VERSION 5.7 ;
BUSBITCHARS "[]" ;
DIVIDERCHAR "/" ;

PROPERTYDEFINITIONS
  LAYER LEF58_TYPE STRING ;
  LAYER LEF58_ENCLOSURE STRING ;
  LAYER LEF58_SPACING STRING ;
  LAYER LEF58_WIDTH STRING ;
END PROPERTYDEFINITIONS

UNITS
  TIME NANOSECONDS 1 ;
  CAPACITANCE PICOFARADS 1 ;
  RESISTANCE OHMS 1 ;
  DATABASE MICRONS 1000 ;
END UNITS
MANUFACTURINGGRID 0.005 ;

SITE core
  SIZE 0.56 BY 5.6 ;
  CLASS CORE ;
  SYMMETRY X Y ;
END core

LAYER OverlapCheck
  TYPE OVERLAP ;
END OverlapCheck

LAYER WN
  TYPE MASTERSLICE ;
  PROPERTY LEF58_TYPE "TYPE NWELL ;" ;
  PROPERTY LEF58_SPACING "SPACING 2.8 ;" ;
  PROPERTY LEF58_WIDTH "WIDTH 0.86 ;" ;
END WN

LAYER ACTIVE
  TYPE MASTERSLICE ;
  PROPERTY LEF58_TYPE "TYPE DIFFUSION ;" ;
END ACTIVE

LAYER XP
  TYPE IMPLANT ;
  WIDTH 0.44 ;
  SPACING 0.44 ;
END XP

LAYER XN
  TYPE IMPLANT ;
  WIDTH 0.44 ;
  SPACING 0.44 ;
END XN

LAYER GC
  TYPE MASTERSLICE ;
END GC

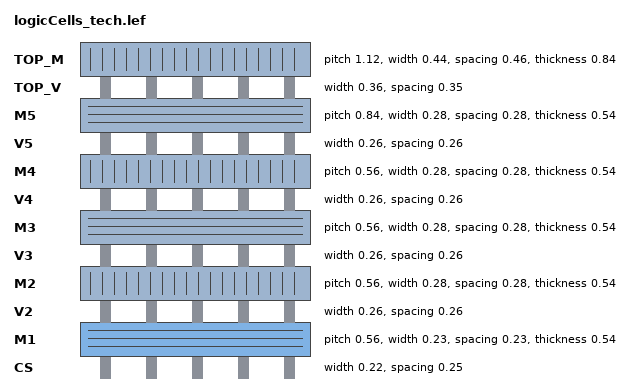
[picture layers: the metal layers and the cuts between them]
LAYER CS
  TYPE CUT ;
  SPACING 0.25 ;
  WIDTH 0.22 ;
  ENCLOSURE BELOW 0.1 0.1 ;
  ENCLOSURE ABOVE 0.06 0.005 ;
  ANTENNAMODEL OXIDE1 ;
END CS

LAYER M1
  TYPE ROUTING ;
  DIRECTION HORIZONTAL ;
  PITCH 0.56 0.56 ;
  WIDTH 0.23 ;
  OFFSET 0.28 ;
  AREA 0.202 ;
  SPACING 0.23 ;
  SPACING 0.6 RANGE 10 10000 ;
  SPACING 0.23 SAMENET ;
  RESISTANCE RPERSQ 0.08 ;
  CAPACITANCE CPERSQDIST 3.51e-05 ;
  HEIGHT 1.05 ;
  THICKNESS 0.54 ;
  ANTENNAMODEL OXIDE1 ;
    ANTENNASIDEAREARATIO 400 ;
    ANTENNADIFFSIDEAREARATIO PWL ( ( 0 400 ) ( 0.203 400 ) ( 0.203001 2281.2 ) ( 1.203 2681.2 ) ) ;
END M1

LAYER V2
  TYPE CUT ;
  SPACING 0.26 ;
  SPACING 0 LAYER CS ;
  WIDTH 0.26 ;
  ENCLOSURE BELOW 0.06 0.01 ;
  ENCLOSURE ABOVE 0.06 0.01 ;
  ANTENNAMODEL OXIDE1 ;
    ANTENNAAREARATIO 20 ;
    ANTENNADIFFAREARATIO PWL ( ( 0 20 ) ( 0.203 20 ) ( 0.203001 91.9161 ) ( 1.203 175.246 ) ) ;
END V2

LAYER M2
  TYPE ROUTING ;
  DIRECTION VERTICAL ;
  PITCH 0.56 0.56 ;
  WIDTH 0.28 ;
  OFFSET 0.28 ;
  AREA 0.202 ;
  SPACING 0.28 ;
  SPACING 0.6 RANGE 10 10000 ;
  SPACING 0.28 SAMENET ;
  RESISTANCE RPERSQ 0.08 ;
  CAPACITANCE CPERSQDIST 1.46e-05 ;
  HEIGHT 2.41 ;
  THICKNESS 0.54 ;
  ANTENNAMODEL OXIDE1 ;
    ANTENNASIDEAREARATIO 400 ;
    ANTENNADIFFSIDEAREARATIO PWL ( ( 0 400 ) ( 0.203 400 ) ( 0.203001 2281.2 ) ( 1.203 2681.2 ) ) ;
END M2

LAYER V3
  TYPE CUT ;
  SPACING 0.26 ;
  SPACING 0 SAMENET LAYER V2 STACK ;
  WIDTH 0.26 ;
  ENCLOSURE BELOW 0.06 0.01 ;
  ENCLOSURE ABOVE 0.06 0.01 ;
  ANTENNAMODEL OXIDE1 ;
    ANTENNAAREARATIO 20 ;
    ANTENNADIFFAREARATIO PWL ( ( 0 20 ) ( 0.203 20 ) ( 0.203001 91.9161 ) ( 1.203 175.246 ) ) ;
END V3

LAYER M3
  TYPE ROUTING ;
  DIRECTION HORIZONTAL ;
  PITCH 0.56 0.56 ;
  WIDTH 0.28 ;
  OFFSET 0.28 ;
  AREA 0.202 ;
  SPACING 0.28 ;
  SPACING 0.6 RANGE 10 10000 ;
  SPACING 0.28 SAMENET ;
  RESISTANCE RPERSQ 0.08 ;
  CAPACITANCE CPERSQDIST 9.24e-06 ;
  HEIGHT 3.77 ;
  THICKNESS 0.54 ;
  ANTENNAMODEL OXIDE1 ;
    ANTENNASIDEAREARATIO 400 ;
    ANTENNADIFFSIDEAREARATIO PWL ( ( 0 400 ) ( 0.203 400 ) ( 0.203001 2281.2 ) ( 1.203 2681.2 ) ) ;
END M3

LAYER V4
  TYPE CUT ;
  SPACING 0.26 ;
  SPACING 0 SAMENET LAYER V3 STACK ;
  WIDTH 0.26 ;
  ENCLOSURE BELOW 0.06 0.01 ;
  ENCLOSURE ABOVE 0.06 0.01 ;
  ANTENNAMODEL OXIDE1 ;
    ANTENNAAREARATIO 20 ;
    ANTENNADIFFAREARATIO PWL ( ( 0 20 ) ( 0.203 20 ) ( 0.203001 91.9161 ) ( 1.203 175.246 ) ) ;
END V4

LAYER M4
  TYPE ROUTING ;
  DIRECTION VERTICAL ;
  PITCH 0.56 0.56 ;
  WIDTH 0.28 ;
  OFFSET 0.28 ;
  AREA 0.202 ;
  SPACING 0.28 ;
  SPACING 0.6 RANGE 10 10000 ;
  SPACING 0.28 SAMENET ;
  RESISTANCE RPERSQ 0.08 ;
  CAPACITANCE CPERSQDIST 6.75e-06 ;
  HEIGHT 5.13 ;
  THICKNESS 0.54 ;
  ANTENNAMODEL OXIDE1 ;
    ANTENNASIDEAREARATIO 400 ;
    ANTENNADIFFSIDEAREARATIO PWL ( ( 0 400 ) ( 0.203 400 ) ( 0.203001 2281.2 ) ( 1.203 2681.2 ) ) ;
END M4

LAYER V5
  TYPE CUT ;
  SPACING 0.26 ;
  SPACING 0 SAMENET LAYER V4 STACK ;
  WIDTH 0.26 ;
  ENCLOSURE BELOW 0.06 0.01 ;
  ENCLOSURE ABOVE 0.06 0.01 ;
  ANTENNAMODEL OXIDE1 ;
    ANTENNAAREARATIO 20 ;
    ANTENNADIFFAREARATIO PWL ( ( 0 20 ) ( 0.203 20 ) ( 0.203001 91.9161 ) ( 1.203 175.246 ) ) ;
END V5

LAYER M5
  TYPE ROUTING ;
  DIRECTION HORIZONTAL ;
  PITCH 0.84 0.84 ;
  WIDTH 0.28 ;
  OFFSET 0.42 ;
  AREA 0.202 ;
  SPACING 0.28 ;
  SPACING 0.6 RANGE 10 10000 ;
  SPACING 0.28 SAMENET ;
  RESISTANCE RPERSQ 0.08 ;
  CAPACITANCE CPERSQDIST 5.32e-06 ;
  HEIGHT 6.49 ;
  THICKNESS 0.54 ;
  ANTENNAMODEL OXIDE1 ;
    ANTENNASIDEAREARATIO 400 ;
    ANTENNADIFFSIDEAREARATIO PWL ( ( 0 400 ) ( 0.203 400 ) ( 0.203001 2281.2 ) ( 1.203 2681.2 ) ) ;
END M5

LAYER TOP_V
  TYPE CUT ;
  SPACING 0.35 ;
  SPACING 0 SAMENET LAYER V5 STACK ;
  WIDTH 0.36 ;
  ENCLOSURE BELOW 0.06 0.01 ;
  ENCLOSURE ABOVE 0.09 0.09 ;
  ANTENNAMODEL OXIDE1 ;
    ANTENNAAREARATIO 20 ;
    ANTENNADIFFAREARATIO PWL ( ( 0 20 ) ( 0.203 20 ) ( 0.203001 91.9161 ) ( 1.203 175.246 ) ) ;
END TOP_V

LAYER TOP_M
  TYPE ROUTING ;
  DIRECTION VERTICAL ;
  PITCH 1.12 1.12 ;
  WIDTH 0.44 ;
  OFFSET 0.56 ;
  AREA 0.562 ;
  SPACING 0.46 ;
  SPACING 0.6 RANGE 10 10000 ;
  SPACING 0.46 SAMENET ;
  RESISTANCE RPERSQ 0.04 ;
  CAPACITANCE CPERSQDIST 4.389e-06 ;
  HEIGHT 7.83 ;
  THICKNESS 0.84 ;
  ANTENNAMODEL OXIDE1 ;
    ANTENNASIDEAREARATIO 400 ;
    ANTENNADIFFSIDEAREARATIO PWL ( ( 0 400 ) ( 0.203 400 ) ( 0.203001 31624 ) ( 1.203 39624 ) ) ;
END TOP_M

VIARULE ML_M5_LD GENERATE
  LAYER M5 ;
    ENCLOSURE 0.1 0.1 ;
  LAYER TOP_M ;
    ENCLOSURE 0.1 0.1 ;
  LAYER TOP_V ;
    RECT -0.18 -0.18 0.18 0.18 ;
    SPACING 0.71 BY 0.71 ;
END ML_M5_LD

VIARULE M5_M4_LD GENERATE
  LAYER M4 ;
    ENCLOSURE 0.1 0.1 ;
  LAYER M5 ;
    ENCLOSURE 0.1 0.1 ;
  LAYER V5 ;
    RECT -0.13 -0.13 0.13 0.13 ;
    SPACING 0.52 BY 0.52 ;
END M5_M4_LD

VIARULE M4_M3_LD GENERATE
  LAYER M3 ;
    ENCLOSURE 0.1 0.1 ;
  LAYER M4 ;
    ENCLOSURE 0.1 0.1 ;
  LAYER V4 ;
    RECT -0.13 -0.13 0.13 0.13 ;
    SPACING 0.52 BY 0.52 ;
END M4_M3_LD

VIARULE M3_M2_LD GENERATE
  LAYER M2 ;
    ENCLOSURE 0.1 0.1 ;
  LAYER M3 ;
    ENCLOSURE 0.1 0.1 ;
  LAYER V3 ;
    RECT -0.13 -0.13 0.13 0.13 ;
    SPACING 0.52 BY 0.52 ;
END M3_M2_LD

VIARULE M2_M1_LD GENERATE
  LAYER M1 ;
    ENCLOSURE 0.1 0.1 ;
  LAYER M2 ;
    ENCLOSURE 0.1 0.1 ;
  LAYER V2 ;
    RECT -0.13 -0.13 0.13 0.13 ;
    SPACING 0.52 BY 0.52 ;
END M2_M1_LD

VIARULE ML_M5_S GENERATE DEFAULT
  LAYER M5 ;
    ENCLOSURE 0.01 0.01 ;
  LAYER TOP_M ;
    ENCLOSURE 0.09 0.09 ;
  LAYER TOP_V ;
    RECT -0.18 -0.18 0.18 0.18 ;
    SPACING 0.71 BY 0.71 ;
END ML_M5_S

VIARULE M5_M4_S GENERATE DEFAULT
  LAYER M4 ;
    ENCLOSURE 0.01 0.01 ;
  LAYER M5 ;
    ENCLOSURE 0.01 0.01 ;
  LAYER V5 ;
    RECT -0.13 -0.13 0.13 0.13 ;
    SPACING 0.52 BY 0.52 ;
END M5_M4_S

VIARULE M4_M3_S GENERATE DEFAULT
  LAYER M3 ;
    ENCLOSURE 0.01 0.01 ;
  LAYER M4 ;
    ENCLOSURE 0.01 0.01 ;
  LAYER V4 ;
    RECT -0.13 -0.13 0.13 0.13 ;
    SPACING 0.52 BY 0.52 ;
END M4_M3_S

VIARULE M3_M2_S GENERATE DEFAULT
  LAYER M2 ;
    ENCLOSURE 0.01 0.01 ;
  LAYER M3 ;
    ENCLOSURE 0.01 0.01 ;
  LAYER V3 ;
    RECT -0.13 -0.13 0.13 0.13 ;
    SPACING 0.52 BY 0.52 ;
END M3_M2_S

VIARULE M2_M1_S GENERATE DEFAULT
  LAYER M1 ;
    ENCLOSURE 0.01 0.01 ;
  LAYER M2 ;
    ENCLOSURE 0.01 0.01 ;
  LAYER V2 ;
    RECT -0.13 -0.13 0.13 0.13 ;
    SPACING 0.52 BY 0.52 ;
END M2_M1_S

VIARULE ML_M5 GENERATE
  LAYER M5 ;
    ENCLOSURE 0.06 0.06 ;
  LAYER TOP_M ;
    ENCLOSURE 0.09 0.09 ;
  LAYER TOP_V ;
    RECT -0.18 -0.18 0.18 0.18 ;
    SPACING 0.71 BY 0.71 ;
END ML_M5

VIARULE M5_M4 GENERATE
  LAYER M4 ;
    ENCLOSURE 0.06 0.06 ;
  LAYER M5 ;
    ENCLOSURE 0.06 0.06 ;
  LAYER V5 ;
    RECT -0.13 -0.13 0.13 0.13 ;
    SPACING 0.52 BY 0.52 ;
END M5_M4

VIARULE M4_M3 GENERATE
  LAYER M3 ;
    ENCLOSURE 0.06 0.06 ;
  LAYER M4 ;
    ENCLOSURE 0.06 0.06 ;
  LAYER V4 ;
    RECT -0.13 -0.13 0.13 0.13 ;
    SPACING 0.52 BY 0.52 ;
END M4_M3

VIARULE M3_M2 GENERATE
  LAYER M2 ;
    ENCLOSURE 0.06 0.06 ;
  LAYER M3 ;
    ENCLOSURE 0.06 0.06 ;
  LAYER V3 ;
    RECT -0.13 -0.13 0.13 0.13 ;
    SPACING 0.52 BY 0.52 ;
END M3_M2

VIARULE M2_M1 GENERATE
  LAYER M1 ;
    ENCLOSURE 0.06 0.06 ;
  LAYER M2 ;
    ENCLOSURE 0.06 0.06 ;
  LAYER V2 ;
    RECT -0.13 -0.13 0.13 0.13 ;
    SPACING 0.52 BY 0.52 ;
END M2_M1

VIARULE M1_PO_4X GENERATE
  LAYER GC ;
    ENCLOSURE 0.1 0.1 ;
  LAYER M1 ;
    ENCLOSURE 0.06 0.06 ;
  LAYER CS ;
    RECT -0.11 -0.11 0.11 0.11 ;
    SPACING 0.5 BY 0.5 ;
END M1_PO_4X

VIARULE M1_PO GENERATE
  LAYER GC ;
    ENCLOSURE 0.1 0.1 ;
  LAYER M1 ;
    ENCLOSURE 0.06 0.06 ;
  LAYER CS ;
    RECT -0.11 -0.11 0.11 0.11 ;
    SPACING 0.47 BY 0.47 ;
END M1_PO

VIARULE PTAP_4X_LG GENERATE
  LAYER ACTIVE ;
    ENCLOSURE 0.1 0.1 ;
  LAYER M1 ;
    ENCLOSURE 0.06 0.06 ;
  LAYER CS ;
    RECT -0.11 -0.11 0.11 0.11 ;
    SPACING 0.5 BY 0.5 ;
END PTAP_4X_LG

VIARULE PTAP_4X GENERATE
  LAYER ACTIVE ;
    ENCLOSURE 0.1 0.1 ;
  LAYER M1 ;
    ENCLOSURE 0.06 0.06 ;
  LAYER CS ;
    RECT -0.11 -0.11 0.11 0.11 ;
    SPACING 0.5 BY 0.5 ;
END PTAP_4X

VIARULE PTAP_LG GENERATE
  LAYER ACTIVE ;
    ENCLOSURE 0.1 0.1 ;
  LAYER M1 ;
    ENCLOSURE 0.06 0.06 ;
  LAYER CS ;
    RECT -0.11 -0.11 0.11 0.11 ;
    SPACING 0.47 BY 0.47 ;
END PTAP_LG

VIARULE PTAP GENERATE
  LAYER ACTIVE ;
    ENCLOSURE 0.1 0.1 ;
  LAYER M1 ;
    ENCLOSURE 0.06 0.06 ;
  LAYER CS ;
    RECT -0.11 -0.11 0.11 0.11 ;
    SPACING 0.47 BY 0.47 ;
END PTAP

VIARULE NTAP_4X_LG GENERATE
  LAYER ACTIVE ;
    ENCLOSURE 0.1 0.1 ;
  LAYER M1 ;
    ENCLOSURE 0.06 0.06 ;
  LAYER CS ;
    RECT -0.11 -0.11 0.11 0.11 ;
    SPACING 0.5 BY 0.5 ;
END NTAP_4X_LG

VIARULE NTAP_4X GENERATE
  LAYER ACTIVE ;
    ENCLOSURE 0.1 0.1 ;
  LAYER M1 ;
    ENCLOSURE 0.06 0.06 ;
  LAYER CS ;
    RECT -0.11 -0.11 0.11 0.11 ;
    SPACING 0.5 BY 0.5 ;
END NTAP_4X

VIARULE NTAP_LG GENERATE
  LAYER ACTIVE ;
    ENCLOSURE 0.1 0.1 ;
  LAYER M1 ;
    ENCLOSURE 0.06 0.06 ;
  LAYER CS ;
    RECT -0.11 -0.11 0.11 0.11 ;
    SPACING 0.47 BY 0.47 ;
END NTAP_LG

VIARULE NTAP GENERATE
  LAYER ACTIVE ;
    ENCLOSURE 0.1 0.1 ;
  LAYER M1 ;
    ENCLOSURE 0.06 0.06 ;
  LAYER CS ;
    RECT -0.11 -0.11 0.11 0.11 ;
    SPACING 0.47 BY 0.47 ;
END NTAP

VIARULE M1_WN GENERATE
  LAYER ACTIVE ;
    ENCLOSURE 0.1 0.1 ;
  LAYER M1 ;
    ENCLOSURE 0.06 0.06 ;
  LAYER CS ;
    RECT -0.11 -0.11 0.11 0.11 ;
    SPACING 0.47 BY 0.47 ;
END M1_WN


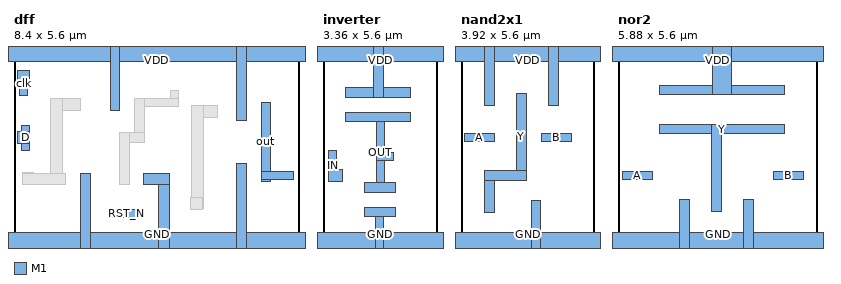
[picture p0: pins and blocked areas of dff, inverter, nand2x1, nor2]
MACRO dff
  CLASS CORE ;
  ORIGIN 0 0 ;
  FOREIGN dff 0 0 ;
  SIZE 8.4 BY 5.6 ;
  SYMMETRY X Y ;
  SITE core ;
  PIN D
    DIRECTION INOUT ;
    USE SIGNAL ;
    PORT
      LAYER M1 ;
        RECT 0.22 2.705 0.45 3.445 ;
        RECT 0.11 2.91 0.45 3.25 ;
    END
  END D
  PIN clk
    DIRECTION INPUT ;
    USE CLOCK ;
    PORT
      LAYER M1 ;
        RECT 0.115 4.705 0.455 5.045 ;
        RECT 0.17 4.32 0.4 5.045 ;
    END
  END clk
  PIN out
    DIRECTION INOUT ;
    USE SIGNAL ;
    PORT
      LAYER M1 ;
        RECT 7.28 1.845 8.24 2.075 ;
        RECT 7.28 1.795 7.56 4.105 ;
    END
  END out
  PIN RST_N
    DIRECTION INPUT ;
    USE SIGNAL ;
    PORT
      LAYER M1 ;
        RECT 2.87 0.725 3.78 0.955 ;
    END
  END RST_N
  PIN VDD
    DIRECTION INOUT ;
    USE POWER ;
    SHAPE ABUTMENT ;
    PORT
      LAYER M1 ;
        RECT -0.28 5.32 8.68 5.88 ;
        RECT 6.56 3.585 6.84 5.88 ;
        RECT 2.835 3.89 3.115 5.88 ;
    END
  END VDD
  PIN GND
    DIRECTION INOUT ;
    USE GROUND ;
    SHAPE ABUTMENT ;
    PORT
      LAYER M1 ;
        RECT -0.28 -0.28 8.68 0.28 ;
        RECT 6.56 -0.28 6.84 2.315 ;
        RECT 3.83 1.685 4.595 2.025 ;
        RECT 4.255 -0.28 4.595 2.025 ;
        RECT 1.96 -0.28 2.24 2.025 ;
    END
  END GND
  OBS
    LAYER M1 ;
      RECT 5.24 3.675 6.01 4.015 ;
      RECT 5.24 0.98 5.58 4.015 ;
      RECT 5.21 0.96 5.55 1.3 ;
      RECT 4.625 4 4.855 4.475 ;
      RECT 3.555 4 4.855 4.23 ;
      RECT 3.555 2.94 3.835 4.23 ;
      RECT 3.11 2.94 3.835 3.22 ;
      RECT 3.11 1.685 3.39 3.22 ;
      RECT 1.075 3.89 1.965 4.23 ;
      RECT 1.075 1.685 1.415 4.23 ;
      RECT 0.245 1.685 0.585 2.04 ;
      RECT 0.245 1.685 1.52 2.025 ;
  END
END dff

MACRO inverter
  CLASS CORE ;
  ORIGIN 0 0 ;
  FOREIGN inverter 0 0 ;
  SIZE 3.36 BY 5.6 ;
  SYMMETRY X Y ;
  SITE core ;
  PIN GND
    DIRECTION INOUT ;
    USE GROUND ;
    SHAPE ABUTMENT ;
    PORT
      LAYER M1 ;
        RECT -0.28 -0.28 3.64 0.28 ;
        RECT 1.23 0.74 2.15 1.02 ;
        RECT 1.56 -0.28 1.79 1.02 ;
    END
  END GND
  PIN OUT
    DIRECTION OUTPUT ;
    USE SIGNAL ;
    PORT
      LAYER M1 ;
        RECT 0.67 3.545 2.59 3.825 ;
        RECT 1.23 1.46 2.15 1.74 ;
        RECT 1.575 2.405 2.075 2.635 ;
        RECT 1.575 1.46 1.805 3.825 ;
    END
  END OUT
  PIN IN
    DIRECTION INPUT ;
    USE SIGNAL ;
    PORT
      LAYER M1 ;
        RECT 0.165 1.79 0.565 2.13 ;
        RECT 0.165 1.79 0.395 2.705 ;
    END
  END IN
  PIN VDD
    DIRECTION INOUT ;
    USE POWER ;
    SHAPE ABUTMENT ;
    PORT
      LAYER M1 ;
        RECT -0.28 5.32 3.64 5.88 ;
        RECT 0.67 4.265 2.59 4.545 ;
        RECT 1.49 4.265 1.77 5.88 ;
    END
  END VDD
END inverter

MACRO nand2x1
  CLASS CORE ;
  ORIGIN 0 0 ;
  FOREIGN nand2x1 0 0 ;
  SIZE 3.92 BY 5.6 ;
  SYMMETRY X Y ;
  SITE core ;
  PIN VDD
    DIRECTION INOUT ;
    USE POWER ;
    SHAPE ABUTMENT ;
    PORT
      LAYER M1 ;
        RECT -0.28 5.32 4.2 5.88 ;
        RECT 2.58 4.03 2.86 5.88 ;
        RECT 0.7 4.03 0.98 5.88 ;
    END
  END VDD
  PIN A
    DIRECTION INPUT ;
    USE SIGNAL ;
    PORT
      LAYER M1 ;
        RECT 0.11 2.965 0.99 3.195 ;
    END
  END A
  PIN Y
    DIRECTION OUTPUT ;
    USE SIGNAL ;
    PORT
      LAYER M1 ;
        RECT 1.64 1.82 1.92 4.37 ;
        RECT 0.7 1.82 1.92 2.1 ;
        RECT 0.7 0.87 0.98 2.1 ;
    END
  END Y
  PIN B
    DIRECTION INPUT ;
    USE SIGNAL ;
    PORT
      LAYER M1 ;
        RECT 2.365 2.965 3.25 3.195 ;
    END
  END B
  PIN GND
    DIRECTION INOUT ;
    USE GROUND ;
    SHAPE ABUTMENT ;
    PORT
      LAYER M1 ;
        RECT -0.28 -0.28 4.2 0.28 ;
        RECT 2.07 -0.28 2.35 1.21 ;
    END
  END GND
END nand2x1

MACRO nor2
  CLASS CORE ;
  ORIGIN 0 0 ;
  FOREIGN nor2 0 0 ;
  SIZE 5.88 BY 5.6 ;
  SYMMETRY X Y ;
  SITE core ;
  PIN GND
    DIRECTION INOUT ;
    USE GROUND ;
    SHAPE ABUTMENT ;
    PORT
      LAYER M1 ;
        RECT -0.28 -0.28 6.16 0.28 ;
        RECT 3.7 -0.28 3.98 1.25 ;
        RECT 1.82 -0.28 2.1 1.25 ;
    END
  END GND
  PIN Y
    DIRECTION OUTPUT ;
    USE SIGNAL ;
    PORT
      LAYER M1 ;
        RECT 1.23 3.19 4.91 3.47 ;
        RECT 2.76 0.91 3.04 3.47 ;
    END
  END Y
  PIN A
    DIRECTION INPUT ;
    USE SIGNAL ;
    PORT
      LAYER M1 ;
        RECT 0.125 1.845 1.01 2.075 ;
    END
  END A
  PIN B
    DIRECTION INPUT ;
    USE SIGNAL ;
    PORT
      LAYER M1 ;
        RECT 4.59 1.845 5.475 2.075 ;
    END
  END B
  PIN VDD
    DIRECTION INOUT ;
    USE POWER ;
    SHAPE ABUTMENT ;
    PORT
      LAYER M1 ;
        RECT -0.28 5.32 6.16 5.88 ;
        RECT 1.23 4.34 4.91 4.62 ;
        RECT 2.795 4.34 3.355 5.88 ;
    END
  END VDD
END nor2


END LIBRARY
